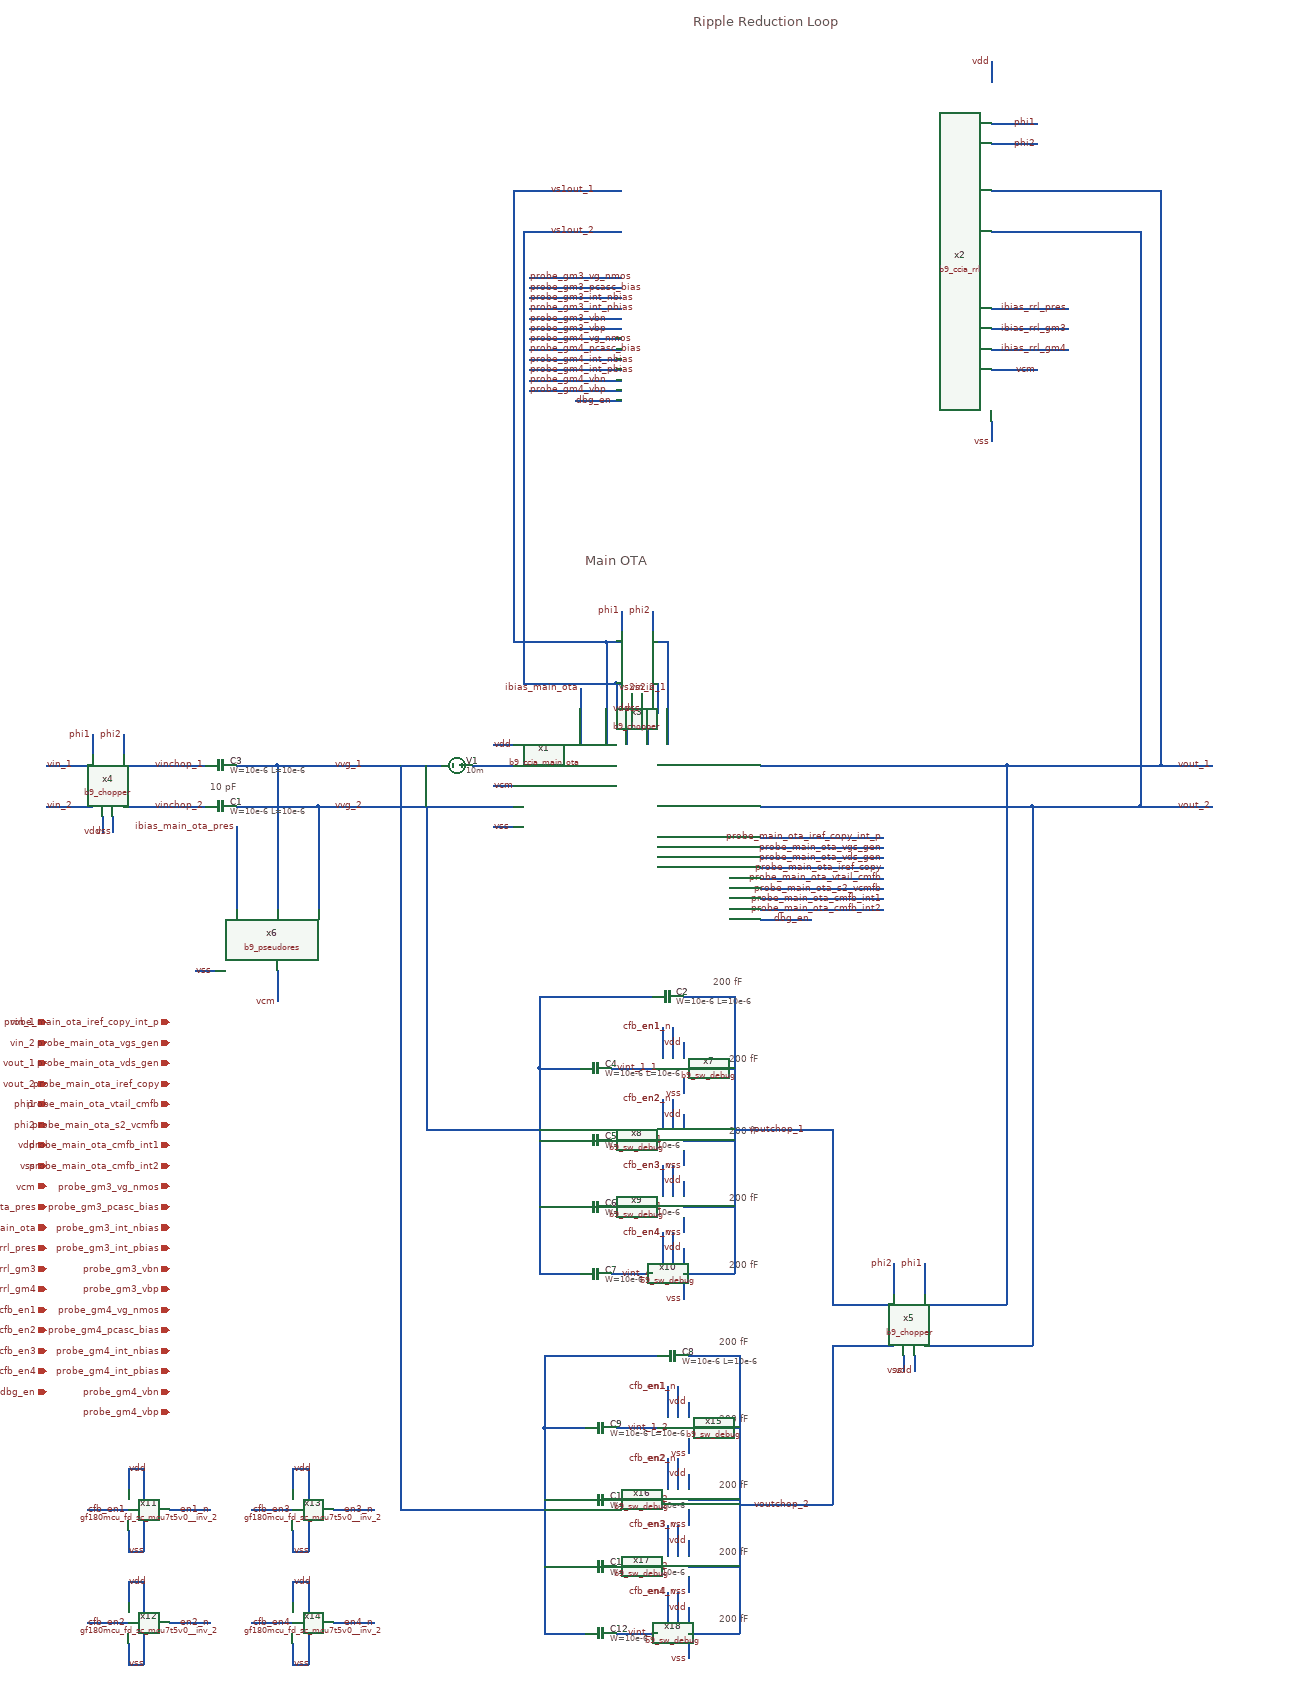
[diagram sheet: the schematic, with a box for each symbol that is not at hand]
v {xschem version=3.4.8RC file_version=1.3}
G {}
K {}
V {}
S {}
F {}
E {}
T {10 pF} 320 -2010 0 0 0.4 0.4 {}
T {Ripple Reduction Loop} 1260 -3500 0 0 0.8 0.8 {}
T {Main OTA} 1050 -2450 0 0 0.8 0.8 {}
T {200 fF} 1300 -1630 0 1 0.4 0.4 {}
T {200 fF} 1330 -1480 0 1 0.4 0.4 {}
T {200 fF} 1330 -1340 0 1 0.4 0.4 {}
T {200 fF} 1330 -1210 0 1 0.4 0.4 {}
T {200 fF} 1330 -1080 0 1 0.4 0.4 {}
T {200 fF} 1310 -930 0 1 0.4 0.4 {}
T {200 fF} 1310 -780 0 1 0.4 0.4 {}
T {200 fF} 1310 -650 0 1 0.4 0.4 {}
T {200 fF} 1310 -520 0 1 0.4 0.4 {}
T {200 fF} 1310 -390 0 1 0.4 0.4 {}
N 1090 -2280 1090 -2080 {lab=vs1out_1}
N 1090 -2280 1120 -2280 {lab=vs1out_1}
N 1130 -2140 1130 -2080 {lab=vs1out_2}
N 1110 -2140 1130 -2140 {lab=vs1out_2}
N 1110 -2200 1110 -2140 {lab=vs1out_2}
N 1110 -2200 1120 -2200 {lab=vs1out_2}
N 1180 -2200 1190 -2200 {lab=vs2in_2}
N 1190 -2200 1190 -2140 {lab=vs2in_2}
N 1170 -2140 1190 -2140 {lab=vs2in_2}
N 1170 -2140 1170 -2090 {lab=vs2in_2}
N 1170 -2090 1170 -2080 {lab=vs2in_2}
N 1180 -2280 1210 -2280 {lab=vs2in_1}
N 1210 -2280 1210 -2080 {lab=vs2in_1}
N 1120 -2340 1120 -2300 {lab=phi1}
N 1180 -2340 1180 -2300 {lab=phi2}
N 1140 -2180 1140 -2150 {lab=vdd}
N 1160 -2180 1160 -2150 {lab=vss}
N 870 -2080 910 -2080 {lab=vdd}
N 870 -1920 910 -1920 {lab=vss}
N 1840 -2710 1840 -2670 {lab=vss}
N 1840 -3410 1840 -3370 {lab=vdd}
N 870 -2000 910 -2000 {lab=vcm}
N 990 -2990 1120 -2990 {lab=probe_gm3_vg_nmos}
N 1080 -2750 1120 -2750 {lab=dbg_en}
N 1390 -1900 1520 -1900 {lab=probe_main_ota_iref_copy_int_p}
N 1390 -1740 1450 -1740 {lab=dbg_en}
N 150 -2040 210 -2040 {lab=vinchop_1}
N 610 -1960 910 -1960 {lab=vvg_2}
N 150 -1960 210 -1960 {lab=vinchop_2}
N 910 -3160 1120 -3160 {lab=vs1out_1}
N 910 -2850 910 -2280 {lab=vs1out_1}
N 910 -2280 1090 -2280 {lab=vs1out_1}
N 950 -3080 1120 -3080 {lab=vs1out_2}
N 930 -2770 930 -2200 {lab=vs1out_2}
N 950 -2200 1110 -2200 {lab=vs1out_2}
N 2170 -2850 2170 -2040 {lab=vout_1}
N 1840 -3160 2170 -3160 {lab=vout_1}
N 2130 -2760 2130 -1960 {lab=vout_2}
N 2130 -3080 2130 -3070 {lab=vout_2}
N 1840 -3080 2130 -3080 {lab=vout_2}
N 1870 -2040 1870 -1460 {lab=vout_1}
N 1920 -1960 1920 -1380 {lab=vout_2}
N 110 -1940 110 -1910 {lab=vdd}
N 130 -1940 130 -1910 {lab=vss}
N 90 -2100 90 -2060 {lab=phi1}
N 150 -2100 150 -2060 {lab=phi2}
N 1690 -890 1690 -860 {lab=vdd}
N 1670 -890 1670 -860 {lab=vss}
N 1710 -1070 1710 -1010 {lab=phi1}
N 1650 -1070 1650 -1010 {lab=phi2}
N 960 -2990 990 -2990 {lab=probe_gm3_vg_nmos}
N 930 -3080 950 -3080 {lab=vs1out_2}
N 930 -2200 950 -2200 {lab=vs1out_2}
N 940 -2990 960 -2990 {lab=probe_gm3_vg_nmos}
N 940 -2970 1120 -2970 {lab=probe_gm3_pcasc_bias}
N 940 -2950 1120 -2950 {lab=probe_gm3_int_nbias}
N 940 -2930 1120 -2930 {lab=probe_gm3_int_pbias}
N 940 -2910 1120 -2910 {lab=probe_gm3_vbn}
N 940 -2890 1120 -2890 {lab=probe_gm3_vbp}
N 940 -2870 1120 -2870 {lab=probe_gm4_vg_nmos}
N 940 -2850 1120 -2850 {lab=probe_gm4_pcasc_bias}
N 940 -2830 1120 -2830 {lab=probe_gm4_int_nbias}
N 940 -2810 1120 -2810 {lab=probe_gm4_int_pbias}
N 940 -2790 1120 -2790 {lab=probe_gm4_vbn}
N 940 -2770 1120 -2770 {lab=probe_gm4_vbp}
N 1030 -2750 1080 -2750 {lab=dbg_en}
N 1390 -2040 1870 -2040 {lab=vout_1}
N 1870 -2040 2170 -2040 {lab=vout_1}
N 1390 -1960 1920 -1960 {lab=vout_2}
N 1920 -1960 2130 -1960 {lab=vout_2}
N 1520 -1900 1630 -1900 {lab=probe_main_ota_iref_copy_int_p}
N 1390 -1880 1630 -1880 {lab=probe_main_ota_vgs_gen}
N 1390 -1860 1630 -1860 {lab=probe_main_ota_vds_gen}
N 1390 -1840 1630 -1840 {lab=probe_main_ota_iref_copy}
N 1390 -1820 1630 -1820 {lab=probe_main_ota_vtail_cmfb}
N 1390 -1800 1630 -1800 {lab=probe_main_ota_s2_vcmfb}
N 1390 -1780 1630 -1780 {lab=probe_main_ota_cmfb_int1}
N 1390 -1760 1630 -1760 {lab=probe_main_ota_cmfb_int2}
N 1450 -1740 1490 -1740 {lab=dbg_en}
N 1040 -2190 1040 -2080 {lab=ibias_main_ota}
N 1840 -2930 1990 -2930 {lab=ibias_rrl_pres}
N 1840 -2890 1990 -2890 {lab=ibias_rrl_gm3}
N 1840 -2850 1990 -2850 {lab=ibias_rrl_gm4}
N 1840 -2810 1930 -2810 {lab=vcm}
N 450 -2040 450 -1760 {lab=vvg_1}
N 450 -2040 610 -2040 {lab=vvg_1}
N 530 -1960 530 -1760 {lab=vvg_2}
N 450 -1640 450 -1580 {lab=vcm}
N 290 -1640 330 -1640 {lab=vss}
N 370 -1820 370 -1760 {lab=ibias_main_ota_pres}
N 370 -1860 370 -1820 {lab=ibias_main_ota_pres}
N 370 -1920 370 -1860 {lab=ibias_main_ota_pres}
N 370 -1960 530 -1960 {lab=vvg_2}
N 530 -1960 610 -1960 {lab=vvg_2}
N 370 -2040 450 -2040 {lab=vvg_1}
N 210 -2040 310 -2040 {lab=vinchop_1}
N 210 -1960 310 -1960 {lab=vinchop_2}
N 2170 -2040 2270 -2040 {lab=vout_1}
N 2130 -1960 2270 -1960 {lab=vout_2}
N 1710 -910 1750 -910 {lab=vout_2}
N 690 -2040 690 -1100 {lab=vvg_1}
N 1870 -1460 1870 -1100 {lab=vout_1}
N 1710 -990 1750 -990 {lab=vout_1}
N 1100 -1450 1180 -1450 {lab=vint_1_1}
N 1240 -1430 1240 -1400 {lab=vss}
N 1240 -1500 1240 -1470 {lab=vdd}
N 1100 -1310 1180 -1310 {lab=vint_2_1}
N 1100 -1180 1180 -1180 {lab=vint_3_1}
N 1100 -1050 1180 -1050 {lab=vint_4_1}
N 960 -1590 1180 -1590 {lab=vvg_2}
N 960 -1590 960 -1450 {lab=vvg_2}
N 960 -1450 1040 -1450 {lab=vvg_2}
N 960 -1450 960 -1050 {lab=vvg_2}
N 960 -1050 1040 -1050 {lab=vvg_2}
N 960 -1180 1040 -1180 {lab=vvg_2}
N 960 -1310 1040 -1310 {lab=vvg_2}
N 1240 -1590 1340 -1590 {lab=voutchop_1}
N 1340 -1590 1340 -1050 {lab=voutchop_1}
N 1240 -1050 1340 -1050 {lab=voutchop_1}
N 1240 -1180 1340 -1180 {lab=voutchop_1}
N 1240 -1310 1340 -1310 {lab=voutchop_1}
N 1240 -1450 1340 -1450 {lab=voutchop_1}
N 1220 -1500 1220 -1470 {lab=en1_n}
N 1200 -1500 1200 -1470 {lab=cfb_en1}
N 1200 -1510 1200 -1500 {lab=cfb_en1}
N 1240 -1290 1240 -1260 {lab=vss}
N 1240 -1360 1240 -1330 {lab=vdd}
N 1240 -1160 1240 -1130 {lab=vss}
N 1240 -1230 1240 -1200 {lab=vdd}
N 1240 -1030 1240 -1000 {lab=vss}
N 1240 -1100 1240 -1070 {lab=vdd}
N 1220 -1530 1220 -1500 {lab=en1_n}
N 1200 -1530 1200 -1510 {lab=cfb_en1}
N 1220 -1360 1220 -1330 {lab=en2_n}
N 1200 -1360 1200 -1330 {lab=cfb_en2}
N 1200 -1370 1200 -1360 {lab=cfb_en2}
N 1220 -1390 1220 -1360 {lab=en2_n}
N 1200 -1390 1200 -1370 {lab=cfb_en2}
N 1220 -1230 1220 -1200 {lab=en3_n}
N 1200 -1230 1200 -1200 {lab=cfb_en3}
N 1200 -1240 1200 -1230 {lab=cfb_en3}
N 1220 -1260 1220 -1230 {lab=en3_n}
N 1200 -1260 1200 -1240 {lab=cfb_en3}
N 1220 -1100 1220 -1070 {lab=en4_n}
N 1200 -1100 1200 -1070 {lab=cfb_en4}
N 1200 -1110 1200 -1100 {lab=cfb_en4}
N 1220 -1130 1220 -1100 {lab=en4_n}
N 1200 -1130 1200 -1110 {lab=cfb_en4}
N 740 -1960 740 -1590 {lab=vvg_2}
N 80 -590 160 -590 {lab=cfb_en1}
N 160 -670 160 -630 {lab=vdd}
N 160 -550 160 -510 {lab=vss}
N 160 -510 190 -510 {lab=vss}
N 190 -570 190 -510 {lab=vss}
N 190 -670 190 -610 {lab=vdd}
N 160 -670 190 -670 {lab=vdd}
N 240 -590 320 -590 {lab=en1_n}
N 80 -370 160 -370 {lab=cfb_en2}
N 160 -450 160 -410 {lab=vdd}
N 160 -330 160 -290 {lab=vss}
N 160 -290 190 -290 {lab=vss}
N 190 -350 190 -290 {lab=vss}
N 190 -450 190 -390 {lab=vdd}
N 160 -450 190 -450 {lab=vdd}
N 240 -370 320 -370 {lab=en2_n}
N 400 -590 480 -590 {lab=cfb_en3}
N 480 -670 480 -630 {lab=vdd}
N 480 -550 480 -510 {lab=vss}
N 480 -510 510 -510 {lab=vss}
N 510 -570 510 -510 {lab=vss}
N 510 -670 510 -610 {lab=vdd}
N 480 -670 510 -670 {lab=vdd}
N 560 -590 640 -590 {lab=en3_n}
N 400 -370 480 -370 {lab=cfb_en4}
N 480 -450 480 -410 {lab=vdd}
N 480 -330 480 -290 {lab=vss}
N 480 -290 510 -290 {lab=vss}
N 510 -350 510 -290 {lab=vss}
N 510 -450 510 -390 {lab=vdd}
N 480 -450 510 -450 {lab=vdd}
N 560 -370 640 -370 {lab=en4_n}
N 1110 -750 1190 -750 {lab=vint_1_2}
N 1250 -730 1250 -700 {lab=vss}
N 1250 -800 1250 -770 {lab=vdd}
N 1110 -610 1190 -610 {lab=vint_2_2}
N 1110 -480 1190 -480 {lab=vint_3_2}
N 1110 -350 1190 -350 {lab=vint_4_2}
N 970 -890 1190 -890 {lab=vvg_1}
N 970 -890 970 -750 {lab=vvg_1}
N 970 -750 1050 -750 {lab=vvg_1}
N 970 -750 970 -350 {lab=vvg_1}
N 970 -350 1050 -350 {lab=vvg_1}
N 970 -480 1050 -480 {lab=vvg_1}
N 970 -610 1050 -610 {lab=vvg_1}
N 1250 -890 1350 -890 {lab=voutchop_2}
N 1350 -890 1350 -350 {lab=voutchop_2}
N 1250 -350 1350 -350 {lab=voutchop_2}
N 1250 -480 1350 -480 {lab=voutchop_2}
N 1250 -610 1350 -610 {lab=voutchop_2}
N 1250 -750 1350 -750 {lab=voutchop_2}
N 1230 -800 1230 -770 {lab=en1_n}
N 1210 -800 1210 -770 {lab=cfb_en1}
N 1210 -810 1210 -800 {lab=cfb_en1}
N 1250 -590 1250 -560 {lab=vss}
N 1250 -660 1250 -630 {lab=vdd}
N 1250 -460 1250 -430 {lab=vss}
N 1250 -530 1250 -500 {lab=vdd}
N 1250 -330 1250 -300 {lab=vss}
N 1250 -400 1250 -370 {lab=vdd}
N 1230 -830 1230 -800 {lab=en1_n}
N 1210 -830 1210 -810 {lab=cfb_en1}
N 1230 -660 1230 -630 {lab=en2_n}
N 1210 -660 1210 -630 {lab=cfb_en2}
N 1210 -670 1210 -660 {lab=cfb_en2}
N 1230 -690 1230 -660 {lab=en2_n}
N 1210 -690 1210 -670 {lab=cfb_en2}
N 1230 -530 1230 -500 {lab=en3_n}
N 1210 -530 1210 -500 {lab=cfb_en3}
N 1210 -540 1210 -530 {lab=cfb_en3}
N 1230 -560 1230 -530 {lab=en3_n}
N 1210 -560 1210 -540 {lab=cfb_en3}
N 1230 -400 1230 -370 {lab=en4_n}
N 1210 -400 1210 -370 {lab=cfb_en4}
N 1210 -410 1210 -400 {lab=cfb_en4}
N 1230 -430 1230 -400 {lab=en4_n}
N 1210 -430 1210 -410 {lab=cfb_en4}
N 690 -1100 690 -890 {lab=vvg_1}
N 1920 -1380 1920 -910 {lab=vout_2}
N 1750 -910 1920 -910 {lab=vout_2}
N 1870 -1100 1870 -990 {lab=vout_1}
N 1750 -990 1870 -990 {lab=vout_1}
N 1340 -1330 1530 -1330 {lab=voutchop_1}
N 1530 -1330 1530 -990 {lab=voutchop_1}
N 1530 -990 1650 -990 {lab=voutchop_1}
N 1530 -910 1650 -910 {lab=voutchop_2}
N 1530 -910 1530 -600 {lab=voutchop_2}
N 1350 -600 1530 -600 {lab=voutchop_2}
N 690 -890 690 -590 {lab=vvg_1}
N 690 -590 970 -590 {lab=vvg_1}
N 750 -1330 960 -1330 {lab=vvg_2}
N 740 -1330 750 -1330 {lab=vvg_2}
N 740 -1590 740 -1330 {lab=vvg_2}
N 910 -3160 910 -2850 {lab=vs1out_1}
N 930 -3080 930 -2770 {lab=vs1out_2}
N 2130 -3070 2130 -2760 {lab=vout_2}
N 2170 -3160 2170 -2850 {lab=vout_1}
N 0 -2040 90 -2040 {lab=vin_1}
N 0 -1960 90 -1960 {lab=vin_2}
N 830 -2040 910 -2040 {lab=#net1}
N 610 -2040 770 -2040 {lab=vvg_1}
N 1840 -3290 1930 -3290 {lab=#net2}
N 1840 -3250 1930 -3250 {lab=#net3}
C {xschem/ccia_main_ota/b9_ccia_main_ota.sym} 910 -1720 0 0 {name=x1}
C {xschem/ccia_rrl/b9_ccia_rrl.sym} 1840 -2650 0 1 {name=x2}
C {title.sym} 160 -40 0 0 {name=l1 author="alang"}
C {xschem/chopper/b9_chopper.sym} 1120 -2180 0 0 {name=x3}
C {xschem/chopper/b9_chopper.sym} 90 -1940 0 0 {name=x4}
C {symbols/cap_mim_2f0fF.sym} 340 -2040 1 1 {name=C3
W=10e-6
L=10e-6
model=cap_mim_2f0fF
spiceprefix=X
m=50
}
C {symbols/cap_mim_2f0fF.sym} 340 -1960 1 0 {name=C1
W=10e-6
L=10e-6
model=cap_mim_2f0fF
spiceprefix=X
m=50
}
C {xschem/chopper/b9_chopper.sym} 1710 -890 0 1 {name=x5}
C {lab_wire.sym} 870 -2080 0 1 {name=p1 sig_type=std_logic lab=vdd}
C {lab_wire.sym} 870 -1920 0 1 {name=p2 sig_type=std_logic lab=vss}
C {lab_wire.sym} 870 -2000 0 1 {name=p3 sig_type=std_logic lab=vcm}
C {lab_wire.sym} 1140 -2150 3 1 {name=p4 sig_type=std_logic lab=vdd}
C {lab_wire.sym} 1160 -2150 3 1 {name=p5 sig_type=std_logic lab=vss}
C {lab_wire.sym} 1120 -2340 3 0 {name=p6 sig_type=std_logic lab=phi1}
C {lab_wire.sym} 1180 -2340 3 0 {name=p7 sig_type=std_logic lab=phi2}
C {lab_wire.sym} 110 -1910 3 1 {name=p8 sig_type=std_logic lab=vdd}
C {lab_wire.sym} 130 -1910 3 1 {name=p9 sig_type=std_logic lab=vss}
C {lab_wire.sym} 90 -2100 3 0 {name=p10 sig_type=std_logic lab=phi1}
C {lab_wire.sym} 150 -2100 3 0 {name=p11 sig_type=std_logic lab=phi2}
C {lab_wire.sym} 1690 -860 3 1 {name=p12 sig_type=std_logic lab=vdd}
C {lab_wire.sym} 1670 -860 3 1 {name=p13 sig_type=std_logic lab=vss}
C {lab_wire.sym} 1710 -1070 1 1 {name=p14 sig_type=std_logic lab=phi1}
C {lab_wire.sym} 1650 -1070 1 1 {name=p15 sig_type=std_logic lab=phi2}
C {lab_wire.sym} 940 -2990 0 1 {name=p16 sig_type=std_logic lab=probe_gm3_vg_nmos}
C {lab_wire.sym} 940 -2970 0 1 {name=p17 sig_type=std_logic lab=probe_gm3_pcasc_bias}
C {lab_wire.sym} 940 -2950 0 1 {name=p18 sig_type=std_logic lab=probe_gm3_int_nbias}
C {lab_wire.sym} 940 -2930 0 1 {name=p19 sig_type=std_logic lab=probe_gm3_int_pbias}
C {lab_wire.sym} 940 -2910 0 1 {name=p20 sig_type=std_logic lab=probe_gm3_vbn}
C {lab_wire.sym} 940 -2890 0 1 {name=p21 sig_type=std_logic lab=probe_gm3_vbp}
C {lab_wire.sym} 940 -2870 0 1 {name=p22 sig_type=std_logic lab=probe_gm4_vg_nmos}
C {lab_wire.sym} 940 -2850 0 1 {name=p23 sig_type=std_logic lab=probe_gm4_pcasc_bias}
C {lab_wire.sym} 940 -2830 0 1 {name=p24 sig_type=std_logic lab=probe_gm4_int_nbias}
C {lab_wire.sym} 940 -2810 0 1 {name=p25 sig_type=std_logic lab=probe_gm4_int_pbias}
C {lab_wire.sym} 940 -2790 0 1 {name=p26 sig_type=std_logic lab=probe_gm4_vbn}
C {lab_wire.sym} 940 -2770 0 1 {name=p27 sig_type=std_logic lab=probe_gm4_vbp}
C {lab_wire.sym} 1030 -2750 0 1 {name=p28 sig_type=std_logic lab=dbg_en}
C {lab_wire.sym} 1630 -1900 0 0 {name=p29 sig_type=std_logic lab=probe_main_ota_iref_copy_int_p}
C {lab_wire.sym} 1630 -1880 0 0 {name=p30 sig_type=std_logic lab=probe_main_ota_vgs_gen}
C {lab_wire.sym} 1630 -1860 0 0 {name=p31 sig_type=std_logic lab=probe_main_ota_vds_gen}
C {lab_wire.sym} 1630 -1840 0 0 {name=p32 sig_type=std_logic lab=probe_main_ota_iref_copy}
C {lab_wire.sym} 1630 -1820 0 0 {name=p33 sig_type=std_logic lab=probe_main_ota_vtail_cmfb}
C {lab_wire.sym} 1630 -1800 0 0 {name=p34 sig_type=std_logic lab=probe_main_ota_s2_vcmfb}
C {lab_wire.sym} 1630 -1780 0 0 {name=p35 sig_type=std_logic lab=probe_main_ota_cmfb_int1}
C {lab_wire.sym} 1630 -1760 0 0 {name=p36 sig_type=std_logic lab=probe_main_ota_cmfb_int2}
C {lab_wire.sym} 1490 -1740 0 0 {name=p37 sig_type=std_logic lab=dbg_en}
C {lab_wire.sym} 1040 -2190 3 0 {name=p38 sig_type=std_logic lab=ibias_main_ota}
C {lab_wire.sym} 1930 -2810 0 0 {name=p39 sig_type=std_logic lab=vcm}
C {lab_wire.sym} 1990 -2850 0 0 {name=p40 sig_type=std_logic lab=ibias_rrl_gm4}
C {lab_wire.sym} 1990 -2890 0 0 {name=p41 sig_type=std_logic lab=ibias_rrl_gm3}
C {lab_wire.sym} 1990 -2930 0 0 {name=p42 sig_type=std_logic lab=ibias_rrl_pres}
C {xschem/pseudores/b9_pseudores.sym} 330 -1640 0 0 {name=x6}
C {lab_wire.sym} 290 -1640 0 1 {name=p43 sig_type=std_logic lab=vss}
C {lab_wire.sym} 450 -1580 3 1 {name=p44 sig_type=std_logic lab=vcm}
C {lab_wire.sym} 370 -1920 3 0 {name=p45 sig_type=std_logic lab=ibias_main_ota_pres}
C {lab_wire.sym} 1840 -3410 3 0 {name=p46 sig_type=std_logic lab=vdd}
C {lab_wire.sym} 1840 -2670 3 1 {name=p47 sig_type=std_logic lab=vss}
C {lab_wire.sym} 0 -2040 0 1 {name=p48 sig_type=std_logic lab=vin_1}
C {lab_wire.sym} 0 -1960 0 1 {name=p49 sig_type=std_logic lab=vin_2}
C {lab_wire.sym} 210 -2040 0 1 {name=p50 sig_type=std_logic lab=vinchop_1}
C {lab_wire.sym} 210 -1960 0 1 {name=p51 sig_type=std_logic lab=vinchop_2}
C {lab_wire.sym} 560 -2040 0 1 {name=p52 sig_type=std_logic lab=vvg_1}
C {lab_wire.sym} 560 -1960 0 1 {name=p53 sig_type=std_logic lab=vvg_2}
C {lab_wire.sym} 2270 -2040 0 0 {name=p54 sig_type=std_logic lab=vout_1}
C {lab_wire.sym} 2270 -1960 0 0 {name=p55 sig_type=std_logic lab=vout_2}
C {lab_wire.sym} 980 -3160 0 1 {name=p58 sig_type=std_logic lab=vs1out_1}
C {lab_wire.sym} 980 -3080 0 1 {name=p59 sig_type=std_logic lab=vs1out_2}
C {lab_wire.sym} 1210 -2190 1 1 {name=p60 sig_type=std_logic lab=vs2in_1}
C {lab_wire.sym} 1190 -2190 1 1 {name=p61 sig_type=std_logic lab=vs2in_2}
C {symbols/cap_mim_2f0fF.sym} 1210 -1590 3 0 {name=C2
W=10e-6
L=10e-6
model=cap_mim_2f0fF
spiceprefix=X
m=1
}
C {symbols/cap_mim_2f0fF.sym} 1070 -1450 3 0 {name=C4
W=10e-6
L=10e-6
model=cap_mim_2f0fF
spiceprefix=X
m=1
}
C {symbols/cap_mim_2f0fF.sym} 1070 -1310 3 0 {name=C5
W=10e-6
L=10e-6
model=cap_mim_2f0fF
spiceprefix=X
m=1
}
C {symbols/cap_mim_2f0fF.sym} 1070 -1180 3 0 {name=C6
W=10e-6
L=10e-6
model=cap_mim_2f0fF
spiceprefix=X
m=1
}
C {symbols/cap_mim_2f0fF.sym} 1070 -1050 3 0 {name=C7
W=10e-6
L=10e-6
model=cap_mim_2f0fF
spiceprefix=X
m=1
}
C {xschem/sw/b9_sw_debug.sym} 1240 -1430 0 1 {name=x7}
C {lab_wire.sym} 1110 -1450 0 1 {name=p63 sig_type=std_logic lab=vint_1_1}
C {lab_wire.sym} 1120 -1310 0 1 {name=p64 sig_type=std_logic lab=vint_2_1}
C {lab_wire.sym} 1120 -1180 0 1 {name=p65 sig_type=std_logic lab=vint_3_1}
C {lab_wire.sym} 1120 -1050 0 1 {name=p66 sig_type=std_logic lab=vint_4_1}
C {lab_wire.sym} 1240 -1400 1 0 {name=p67 sig_type=std_logic lab=vss}
C {lab_wire.sym} 1240 -1500 1 1 {name=p68 sig_type=std_logic lab=vdd}
C {lab_wire.sym} 1200 -1530 1 1 {name=p69 sig_type=std_logic lab=cfb_en1}
C {xschem/sw/b9_sw_debug.sym} 1240 -1290 0 1 {name=x8}
C {lab_wire.sym} 1240 -1260 1 0 {name=p70 sig_type=std_logic lab=vss}
C {lab_wire.sym} 1240 -1360 1 1 {name=p71 sig_type=std_logic lab=vdd}
C {xschem/sw/b9_sw_debug.sym} 1240 -1160 0 1 {name=x9}
C {lab_wire.sym} 1240 -1130 1 0 {name=p72 sig_type=std_logic lab=vss}
C {lab_wire.sym} 1240 -1230 1 1 {name=p74 sig_type=std_logic lab=vdd}
C {xschem/sw/b9_sw_debug.sym} 1240 -1030 0 1 {name=x10}
C {lab_wire.sym} 1240 -1000 3 1 {name=p75 sig_type=std_logic lab=vss}
C {lab_wire.sym} 1240 -1100 1 1 {name=p76 sig_type=std_logic lab=vdd}
C {lab_wire.sym} 1220 -1530 1 1 {name=p77 sig_type=std_logic lab=en1_n}
C {lab_wire.sym} 1220 -1390 1 1 {name=p79 sig_type=std_logic lab=en2_n}
C {lab_wire.sym} 1220 -1260 1 1 {name=p81 sig_type=std_logic lab=en3_n}
C {lab_wire.sym} 1220 -1130 1 1 {name=p83 sig_type=std_logic lab=en4_n}
C {xschem/mcu7t5v0/gf180mcu_fd_sc_mcu7t5v0__inv_2.sym} 160 -550 0 0 {name=x11}
C {lab_wire.sym} 80 -590 0 1 {name=p57 sig_type=std_logic lab=cfb_en1}
C {lab_wire.sym} 320 -590 0 0 {name=p62 sig_type=std_logic lab=en1_n}
C {lab_wire.sym} 160 -670 0 1 {name=p84 sig_type=std_logic lab=vdd}
C {lab_wire.sym} 160 -510 2 0 {name=p85 sig_type=std_logic lab=vss}
C {xschem/mcu7t5v0/gf180mcu_fd_sc_mcu7t5v0__inv_2.sym} 160 -330 0 0 {name=x12}
C {lab_wire.sym} 80 -370 0 1 {name=p86 sig_type=std_logic lab=cfb_en2}
C {lab_wire.sym} 320 -370 0 0 {name=p87 sig_type=std_logic lab=en2_n}
C {lab_wire.sym} 160 -450 0 1 {name=p88 sig_type=std_logic lab=vdd}
C {lab_wire.sym} 160 -290 2 0 {name=p89 sig_type=std_logic lab=vss}
C {xschem/mcu7t5v0/gf180mcu_fd_sc_mcu7t5v0__inv_2.sym} 480 -550 0 0 {name=x13}
C {lab_wire.sym} 400 -590 0 1 {name=p90 sig_type=std_logic lab=cfb_en3}
C {lab_wire.sym} 640 -590 0 0 {name=p91 sig_type=std_logic lab=en3_n}
C {lab_wire.sym} 480 -670 0 1 {name=p92 sig_type=std_logic lab=vdd}
C {lab_wire.sym} 480 -510 2 0 {name=p93 sig_type=std_logic lab=vss}
C {xschem/mcu7t5v0/gf180mcu_fd_sc_mcu7t5v0__inv_2.sym} 480 -330 0 0 {name=x14}
C {lab_wire.sym} 400 -370 0 1 {name=p94 sig_type=std_logic lab=cfb_en4}
C {lab_wire.sym} 640 -370 0 0 {name=p95 sig_type=std_logic lab=en4_n}
C {lab_wire.sym} 480 -450 0 1 {name=p96 sig_type=std_logic lab=vdd}
C {lab_wire.sym} 480 -290 2 0 {name=p97 sig_type=std_logic lab=vss}
C {symbols/cap_mim_2f0fF.sym} 1220 -890 3 0 {name=C8
W=10e-6
L=10e-6
model=cap_mim_2f0fF
spiceprefix=X
m=1
}
C {symbols/cap_mim_2f0fF.sym} 1080 -750 3 0 {name=C9
W=10e-6
L=10e-6
model=cap_mim_2f0fF
spiceprefix=X
m=1
}
C {symbols/cap_mim_2f0fF.sym} 1080 -610 3 0 {name=C10
W=10e-6
L=10e-6
model=cap_mim_2f0fF
spiceprefix=X
m=1
}
C {symbols/cap_mim_2f0fF.sym} 1080 -480 3 0 {name=C11
W=10e-6
L=10e-6
model=cap_mim_2f0fF
spiceprefix=X
m=1
}
C {symbols/cap_mim_2f0fF.sym} 1080 -350 3 0 {name=C12
W=10e-6
L=10e-6
model=cap_mim_2f0fF
spiceprefix=X
m=1
}
C {xschem/sw/b9_sw_debug.sym} 1250 -730 0 1 {name=x15}
C {lab_wire.sym} 1130 -750 0 1 {name=p98 sig_type=std_logic lab=vint_1_2}
C {lab_wire.sym} 1130 -610 0 1 {name=p99 sig_type=std_logic lab=vint_2_2}
C {lab_wire.sym} 1130 -480 0 1 {name=p100 sig_type=std_logic lab=vint_3_2}
C {lab_wire.sym} 1130 -350 0 1 {name=p101 sig_type=std_logic lab=vint_4_2}
C {lab_wire.sym} 1250 -700 1 0 {name=p102 sig_type=std_logic lab=vss}
C {lab_wire.sym} 1250 -800 1 1 {name=p103 sig_type=std_logic lab=vdd}
C {xschem/sw/b9_sw_debug.sym} 1250 -590 0 1 {name=x16}
C {lab_wire.sym} 1250 -560 1 0 {name=p105 sig_type=std_logic lab=vss}
C {lab_wire.sym} 1250 -660 1 1 {name=p106 sig_type=std_logic lab=vdd}
C {xschem/sw/b9_sw_debug.sym} 1250 -460 0 1 {name=x17}
C {lab_wire.sym} 1250 -430 1 0 {name=p107 sig_type=std_logic lab=vss}
C {lab_wire.sym} 1250 -530 1 1 {name=p108 sig_type=std_logic lab=vdd}
C {xschem/sw/b9_sw_debug.sym} 1250 -330 0 1 {name=x18}
C {lab_wire.sym} 1250 -300 3 1 {name=p109 sig_type=std_logic lab=vss}
C {lab_wire.sym} 1250 -400 1 1 {name=p110 sig_type=std_logic lab=vdd}
C {lab_wire.sym} 1230 -830 1 1 {name=p111 sig_type=std_logic lab=en1_n}
C {lab_wire.sym} 1230 -690 1 1 {name=p113 sig_type=std_logic lab=en2_n}
C {lab_wire.sym} 1230 -560 1 1 {name=p115 sig_type=std_logic lab=en3_n}
C {lab_wire.sym} 1230 -430 1 1 {name=p117 sig_type=std_logic lab=en4_n}
C {lab_wire.sym} 1200 -1390 1 1 {name=p56 sig_type=std_logic lab=cfb_en2}
C {lab_wire.sym} 1200 -1260 1 1 {name=p73 sig_type=std_logic lab=cfb_en3}
C {lab_wire.sym} 1200 -1130 1 1 {name=p78 sig_type=std_logic lab=cfb_en4}
C {lab_wire.sym} 1210 -830 1 1 {name=p80 sig_type=std_logic lab=cfb_en1}
C {lab_wire.sym} 1210 -690 1 1 {name=p104 sig_type=std_logic lab=cfb_en2}
C {lab_wire.sym} 1210 -560 1 1 {name=p112 sig_type=std_logic lab=cfb_en3}
C {lab_wire.sym} 1210 -430 1 1 {name=p114 sig_type=std_logic lab=cfb_en4}
C {lab_wire.sym} 1480 -1330 0 0 {name=p82 sig_type=std_logic lab=voutchop_1}
C {lab_wire.sym} 1490 -600 0 0 {name=p116 sig_type=std_logic lab=voutchop_2}
C {iopin.sym} 0 -1500 0 0 {name=p119 lab=vin_2}
C {iopin.sym} 0 -1540 0 0 {name=p118 lab=vin_1}
C {iopin.sym} 0 -1420 0 0 {name=p120 lab=vout_2}
C {iopin.sym} 0 -1460 0 0 {name=p121 lab=vout_1}
C {iopin.sym} 0 -1340 0 0 {name=p122 lab=phi2}
C {iopin.sym} 0 -1380 0 0 {name=p123 lab=phi1}
C {iopin.sym} 0 -1260 0 0 {name=p124 lab=vss}
C {iopin.sym} 0 -1300 0 0 {name=p125 lab=vdd}
C {iopin.sym} 0 -1220 0 0 {name=p126 lab=vcm}
C {iopin.sym} 0 -1180 0 0 {name=p127 lab=ibias_main_ota_pres}
C {iopin.sym} 0 -1140 0 0 {name=p128 lab=ibias_main_ota}
C {iopin.sym} 0 -1100 0 0 {name=p129 lab=ibias_rrl_pres}
C {iopin.sym} 0 -1060 0 0 {name=p130 lab=ibias_rrl_gm3}
C {iopin.sym} 0 -1020 0 0 {name=p131 lab=ibias_rrl_gm4}
C {iopin.sym} 0 -980 0 0 {name=p132 lab=cfb_en1}
C {iopin.sym} 0 -940 0 0 {name=p133 lab=cfb_en2}
C {iopin.sym} 0 -900 0 0 {name=p134 lab=cfb_en3}
C {iopin.sym} 0 -860 0 0 {name=p135 lab=cfb_en4}
C {iopin.sym} 240 -1540 0 0 {name=p136 lab=probe_main_ota_iref_copy_int_p}
C {iopin.sym} 240 -1500 0 0 {name=p137 lab=probe_main_ota_vgs_gen}
C {iopin.sym} 240 -1460 0 0 {name=p138 lab=probe_main_ota_vds_gen}
C {iopin.sym} 240 -1420 0 0 {name=p139 lab=probe_main_ota_iref_copy}
C {iopin.sym} 240 -1380 0 0 {name=p140 lab=probe_main_ota_vtail_cmfb}
C {iopin.sym} 240 -1340 0 0 {name=p141 lab=probe_main_ota_s2_vcmfb}
C {iopin.sym} 240 -1300 0 0 {name=p142 lab=probe_main_ota_cmfb_int1}
C {iopin.sym} 240 -1260 0 0 {name=p143 lab=probe_main_ota_cmfb_int2}
C {iopin.sym} 240 -1220 0 0 {name=p144 lab=probe_gm3_vg_nmos}
C {iopin.sym} 240 -1180 0 0 {name=p145 lab=probe_gm3_pcasc_bias}
C {iopin.sym} 240 -1140 0 0 {name=p146 lab=probe_gm3_int_nbias}
C {iopin.sym} 240 -1100 0 0 {name=p147 lab=probe_gm3_int_pbias}
C {iopin.sym} 240 -1060 0 0 {name=p148 lab=probe_gm3_vbn}
C {iopin.sym} 240 -1020 0 0 {name=p149 lab=probe_gm3_vbp}
C {iopin.sym} 240 -980 0 0 {name=p150 lab=probe_gm4_vg_nmos}
C {iopin.sym} 240 -940 0 0 {name=p151 lab=probe_gm4_pcasc_bias}
C {iopin.sym} 240 -900 0 0 {name=p152 lab=probe_gm4_int_nbias}
C {iopin.sym} 240 -860 0 0 {name=p153 lab=probe_gm4_int_pbias}
C {iopin.sym} 240 -820 0 0 {name=p154 lab=probe_gm4_vbn}
C {iopin.sym} 240 -780 0 0 {name=p155 lab=probe_gm4_vbp}
C {iopin.sym} 0 -820 0 0 {name=p156 lab=dbg_en}
C {vsource.sym} 800 -2040 1 0 {name=V1 value=10m savecurrent=false}
C {lab_wire.sym} 1930 -3290 0 0 {name=p157 sig_type=std_logic lab=phi1}
C {lab_wire.sym} 1930 -3250 0 0 {name=p158 sig_type=std_logic lab=phi2}
